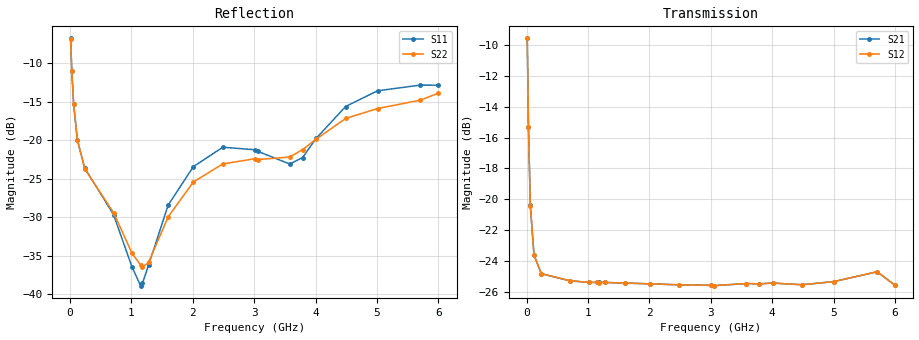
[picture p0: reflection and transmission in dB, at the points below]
! Integrated Device Technology
! Corporate Headquarters
! 6024 Silver Creek Valley Road
! San Jose, CA 95138  USA
! Phone:  1-408-284-8200
! Toll Free:  1-800-223-1366
! Webpage:  http://www.idt.com/
! Timing and RF Division
! 515 Groton Road, Suite 102
! Westford, MA 01886-6024
! Device:  F1951
! Description: 6-bit 0.5 dB Digital Step Attenuator
! Frequency:  100.0 -  4000.00 MHz
! Package:  4x4 mm Thin QFN Plastic Package: 24 pin
! Ports:  2 RF, 6 DC
!  Pin  1  = NC
!  Pin  2  = RF1  =  Port 1
!  Pin  3  = GND
!  Pin  4  = NC
!  Pin  5  = Serial Data Out (SDO)
!  Pin  6  = NC
!  Pin  7  = Reset Bar ( RSTb)
!  Pin  8  = Clock (CLK)
!  Pin  9  = Chip Select Bar (CSb)
!  Pin 10  = NC
!  Pin 11  = Serial Data In (SDI)
!  Pin 12  = NC
!  Pin 13  = NC
!  Pin 14  = VDD
!  Pin 15  = NC
!  Pin 16  = GND
!  Pin 17  = RF2  =  Port 2
!  Pin 18  = NC
!  Pin 19  = GND
!  Pin 20  = GND
!  Pin 21  = GND
!  Pin 22  = GND
!  Pin 23  = GND
!  Pin 24  = GND
! State:  49
! Atten State:  24.5 dB
! Voltage:  +3.30 Volts
! Current:  0.491 mA
! Data:  The device was measured on a F195X evaluation board which has
!  individual transmission lines to the RF pins.  Data was collected
!  de-embedded using a Automatic Fixture Removal [AFR] (Keysight Technologies).
!  The reference plane is the edge of the package pin.
! Misc:  Lot Code  1225BCA
!  Action Tracker AT0399
! Date Measured:  2018-09-13
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# GHz S dB R 50
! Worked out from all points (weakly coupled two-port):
!   600 points, 10 MHz to 6 GHz, reference 50 ohm
!   highest |S21| = -9.56 dB at 10 MHz (marker M1); lowest = -25.6 dB at 3.06 GHz (marker M2)
!   lowest |S11| = -38.9 dB at 1.15 GHz (marker M3), VSWR 1.02, Z = 48.9 + j0.213 ohm
!   |S11| at or under -10 dB: 25.05 MHz to end of sweep
!   |S22| runs from -36.5 to -6.8 dB; largest |S21 - S12| = 0.0002
!   S11 on the Smith chart (normalised r, x): 10 MHz: 1.86, -1.11; 30 MHz: 1.13, -0.61; 60 MHz: 0.99, -0.35; 1.18 GHz: 0.98, +0.01; 6 GHz: 0.80, +0.36
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0.01  -6.78 -31.1  -9.56 -31.9  -9.56 -31.9  -6.83 -31.1
0.03  -10.99 -61.7  -15.32 -53.5  -15.32 -53.6  -11.05 -61.7
0.06  -15.28 -82.2  -20.41 -49.4  -20.42 -49.4  -15.37 -82.4
0.12  -19.92 -102.9  -23.63 -33.5  -23.63 -33.5  -19.97 -102.9
0.24  -23.61 -121.7  -24.84 -20.7  -24.84 -20.6  -23.74 -121.9
0.71  -29.68 -134.0  -25.31 -15.1  -25.30 -15.2  -29.43 -137.4
1.01  -36.47 -152.5  -25.40 -17.0  -25.40 -17.0  -34.68 -151.4
1.15  -38.91 168.9  -25.41 -18.0  -25.41 -17.9  -36.21 -172.3
1.18  -38.62 158.6  -25.41 -18.2  -25.42 -18.2  -36.51 -178.6
1.28  -36.25 132.8  -25.41 -19.1  -25.41 -19.1  -35.89 161.7
1.6  -28.43 116.5  -25.45 -22.3  -25.45 -22.3  -29.96 134.7
2.01  -23.45 124.4  -25.50 -26.8  -25.50 -26.8  -25.44 135.4
2.49  -20.92 137.3  -25.57 -32.0  -25.56 -32.0  -23.09 142.6
3.01  -21.25 147.6  -25.60 -37.4  -25.60 -37.3  -22.42 146.0
3.06  -21.46 147.0  -25.62 -37.7  -25.61 -37.6  -22.52 145.1
3.58  -23.10 127.0  -25.48 -43.3  -25.48 -43.3  -22.20 129.0
3.79  -22.26 111.2  -25.50 -45.6  -25.50 -45.5  -21.23 122.1
4.01  -19.77 102.3  -25.45 -47.9  -25.45 -47.9  -19.88 116.7
4.49  -15.64 100.1  -25.56 -52.6  -25.56 -52.5  -17.19 114.7
5.01  -13.59 108.8  -25.35 -55.8  -25.35 -55.8  -15.90 117.2
5.71  -12.85 113.6  -24.72 -66.9  -24.71 -66.9  -14.80 110.1
6  -12.87 107.5  -25.59 -69.5  -25.59 -69.5  -13.91 106.2
